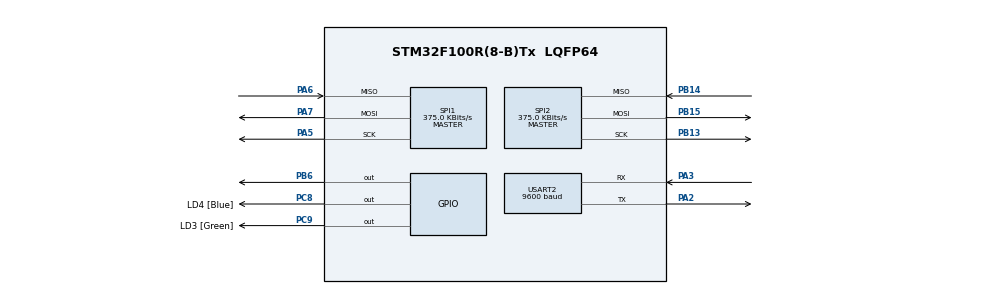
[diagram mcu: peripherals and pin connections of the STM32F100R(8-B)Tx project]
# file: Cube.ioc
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Mcu.Family=STM32F1
Mcu.Name=STM32F100R(8-B)Tx
Mcu.Package=LQFP64
NVIC.PriorityGroup=NVIC_PRIORITYGROUP_4
NVIC.USART2_IRQn=true\:0\:0\:false\:false\:true\:true
PA0-WKUP.Mode=SYS_WakeUp0
PA0-WKUP.Signal=SYS_WKUP
PA13.GPIO_Label=TMS_SWDIO
PA13.Mode=Serial_Wire
PA13.Signal=SYS_JTMS-SWDIO
PA14.GPIO_Label=TCK_SWCLK
PA14.Mode=Serial_Wire
PA14.Signal=SYS_JTCK-SWCLK
PA2.Mode=Asynchronous
PA2.Signal=USART2_TX
PA3.Mode=Asynchronous
PA3.Signal=USART2_RX
PA5.Mode=Full_Duplex_Master
PA5.Signal=SPI1_SCK
PA6.Mode=Full_Duplex_Master
PA6.Signal=SPI1_MISO
PA7.Mode=Full_Duplex_Master
PA7.Signal=SPI1_MOSI
PB13.Mode=Full_Duplex_Master
PB13.Signal=SPI2_SCK
PB14.Mode=Full_Duplex_Master
PB14.Signal=SPI2_MISO
PB15.Mode=Full_Duplex_Master
PB15.Signal=SPI2_MOSI
PB6.Signal=GPIO_Output
PC14-OSC32_IN.Mode=LSE-External-Oscillator
PC14-OSC32_IN.Signal=RCC_OSC32_IN
PC15-OSC32_OUT.Mode=LSE-External-Oscillator
PC15-OSC32_OUT.Signal=RCC_OSC32_OUT
PC8.GPIO_Label=LD4 [Blue]
PC8.Signal=GPIO_Output
PC9.GPIO_Label=LD3 [Green]
PC9.Signal=GPIO_Output
PD0-OSC_IN.Mode=HSE-External-Oscillator
PD0-OSC_IN.Signal=RCC_OSC_IN
PD1-OSC_OUT.Mode=HSE-External-Oscillator
PD1-OSC_OUT.Signal=RCC_OSC_OUT
ProjectManager.HeapSize=0x200
ProjectManager.StackSize=0x400
ProjectManager.TargetToolchain=MDK-ARM V5
RCC.AHBFreq_Value=24000000
RCC.APB1Freq_Value=24000000
RCC.APB1TimFreq_Value=24000000
RCC.APB2Freq_Value=24000000
RCC.APB2TimFreq_Value=24000000
RCC.HCLKFreq_Value=24000000
RCC.PLLMUL=RCC_PLL_MUL3
RCC.PLLSource=RCC_PLLSOURCE_HSE
RCC.SYSCLKFreq_VALUE=24000000
RCC.SYSCLKSource=RCC_SYSCLKSOURCE_PLLCLK
SPI1.BaudRatePrescaler=SPI_BAUDRATEPRESCALER_64
SPI1.CLKPhase=SPI_PHASE_2EDGE
SPI1.CLKPolarity=SPI_POLARITY_HIGH
SPI1.CalculateBaudRate=375.0 KBits/s
SPI1.Direction=SPI_DIRECTION_2LINES
SPI1.Mode=SPI_MODE_MASTER
SPI1.VirtualType=VM_MASTER
SPI2.BaudRatePrescaler=SPI_BAUDRATEPRESCALER_64
SPI2.CLKPhase=SPI_PHASE_2EDGE
SPI2.CLKPolarity=SPI_POLARITY_HIGH
SPI2.CalculateBaudRate=375.0 KBits/s
SPI2.Direction=SPI_DIRECTION_2LINES
SPI2.Mode=SPI_MODE_MASTER
SPI2.VirtualType=VM_MASTER
USART2.BaudRate=9600
USART2.VirtualMode=VM_ASYNC
board=STM32VLDISCOVERY

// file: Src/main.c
/* USER CODE BEGIN Header */
/**
  ******************************************************************************
  * @file           : main.c
  * @brief          : Main program body
  ******************************************************************************
  ** This notice applies to any and all portions of this file
  * that are not between comment pairs USER CODE BEGIN and
  * USER CODE END. Other portions of this file, whether
  * inserted by the user or by software development tools
  * are owned by their respective copyright owners.
  *
  * COPYRIGHT(c) 2019 STMicroelectronics
  *
  * Redistribution and use in source and binary forms, with or without modification,
  * are permitted provided that the following conditions are met:
  *   1. Redistributions of source code must retain the above copyright notice,
  *      this list of conditions and the following disclaimer.
  *   2. Redistributions in binary form must reproduce the above copyright notice,
  *      this list of conditions and the following disclaimer in the documentation
  *      and/or other materials provided with the distribution.
  *   3. Neither the name of STMicroelectronics nor the names of its contributors
  *      may be used to endorse or promote products derived from this software
  *      without specific prior written permission.
  *
  * THIS SOFTWARE IS PROVIDED BY THE COPYRIGHT HOLDERS AND CONTRIBUTORS "AS IS"
  * AND ANY EXPRESS OR IMPLIED WARRANTIES, INCLUDING, BUT NOT LIMITED TO, THE
  * IMPLIED WARRANTIES OF MERCHANTABILITY AND FITNESS FOR A PARTICULAR PURPOSE ARE
  * DISCLAIMED. IN NO EVENT SHALL THE COPYRIGHT HOLDER OR CONTRIBUTORS BE LIABLE
  * FOR ANY DIRECT, INDIRECT, INCIDENTAL, SPECIAL, EXEMPLARY, OR CONSEQUENTIAL
  * DAMAGES (INCLUDING, BUT NOT LIMITED TO, PROCUREMENT OF SUBSTITUTE GOODS OR
  * SERVICES; LOSS OF USE, DATA, OR PROFITS; OR BUSINESS INTERRUPTION) HOWEVER
  * CAUSED AND ON ANY THEORY OF LIABILITY, WHETHER IN CONTRACT, STRICT LIABILITY,
  * OR TORT (INCLUDING NEGLIGENCE OR OTHERWISE) ARISING IN ANY WAY OUT OF THE USE
  * OF THIS SOFTWARE, EVEN IF ADVISED OF THE POSSIBILITY OF SUCH DAMAGE.
  *
  ******************************************************************************
  */
/* USER CODE END Header */

#include "main.h"

/* USER CODE BEGIN Includes */
#include <string.h>
#include "uart.h"
/* USER CODE END Includes */

SPI_HandleTypeDef hspi1;
SPI_HandleTypeDef hspi2;

UART_HandleTypeDef huart2;

/* USER CODE BEGIN PV */
uint8_t data_rec[6];
char num[10];
int16_t x,y,z;
float xg, yg, zg;
/* USER CODE END PV */

void SystemClock_Config(void);
static void MX_GPIO_Init(void);
static void MX_SPI1_Init(void);
static void MX_SPI2_Init(void);
static void MX_USART2_UART_Init(void);

/* USER CODE BEGIN 0 */
void adxl_write (uint8_t address, uint8_t value)
{
	uint8_t data[2];
	data[0] = address|0x40;  // multibyte write enabled
	data[1] = value;
	HAL_GPIO_WritePin (GPIOB, GPIO_PIN_6, GPIO_PIN_RESET); // pull the cs pin low to enable the slave
	HAL_SPI_Transmit (&hspi2, data, 2, 100);  // transmit the address and data
	HAL_GPIO_WritePin (GPIOB, GPIO_PIN_6, GPIO_PIN_SET); // pull the cs pin high to disable the slave
}

void adxl_read (uint8_t address)
{
	address |= 0x80;  // read operation
	address |= 0x40;  // multibyte read
	HAL_GPIO_WritePin (GPIOB, GPIO_PIN_6, GPIO_PIN_RESET);  // pull the cs pin low to enable the slave
	HAL_SPI_Transmit (&hspi2, &address, 1, 100);  // send the address from where you want to read data
	HAL_SPI_Receive (&hspi2, data_rec, 6, 100);  // read 6 BYTES of data
	HAL_GPIO_WritePin (GPIOB, GPIO_PIN_6, GPIO_PIN_SET);  // pull the cs pin high to disable the slave
}

void adxl_init (void)
{
	adxl_write (0x31, 0x01);  // data_format range= +- 4g
	adxl_write (0x2d, 0x00);  // reset all bits
	adxl_write (0x2d, 0x08);  // power_cntl measure and wake up 8hz
}
/* USER CODE END 0 */

int main(void)
{

  /* MCU Configuration--------------------------------------------------------*/

  /* Reset of all peripherals, Initializes the Flash interface and the Systick. */
  HAL_Init();

  /* Configure the system clock */
  SystemClock_Config();

  /* Initialize all configured peripherals */
  MX_GPIO_Init();
  MX_SPI1_Init();
  MX_SPI2_Init();
  MX_USART2_UART_Init();
  /* USER CODE BEGIN 2 */

	adxl_init();  // initialise adxl
  /* USER CODE END 2 */
	print_str("Let the accelerometer be blessed \n\r");
	HAL_Delay(500);
  /* Infinite loop */
  while (1)
  {

    /* USER CODE BEGIN 3 */
//		uint8_t address =45;
//		HAL_GPIO_WritePin (GPIOB, GPIO_PIN_6, GPIO_PIN_RESET); // pull the cs pin low to enable the slave
//		HAL_SPI_Transmit (&hspi2, &address, 1, 100);  // send the address from where you want to read data
//		HAL_GPIO_WritePin (GPIOB, GPIO_PIN_6, GPIO_PIN_SET); // pull the cs pin high to disable the slave

//
		adxl_read (0x32);
	  x = ((data_rec[1]<<8)|data_rec[0]);
    y = ((data_rec[3]<<8)|data_rec[2]);
    z = ((data_rec[5]<<8)|data_rec[4]);

      // Convert into 'g'

    xg = x*.0078;
    yg = y*.0078;
 	  zg = z*.0078;

		print_str("X: ");
		sprintf(num,"%f", xg);
		print_str(num);
		print_str("   Y: ");
		sprintf(num,"%f", yg);
		print_str(num);
		print_str("   Z: ");
		sprintf(num,"%f", zg);
		print_str(num);
		print_str("\n\r");

HAL_Delay (200);   // wait for 200 ms
   	  // display the result on LCD
  }
  /* USER CODE END 3 */
}

void SystemClock_Config(void)
{
  RCC_OscInitTypeDef RCC_OscInitStruct = {0};
  RCC_ClkInitTypeDef RCC_ClkInitStruct = {0};

  /**Initializes the CPU, AHB and APB busses clocks
  */
  RCC_OscInitStruct.OscillatorType = RCC_OSCILLATORTYPE_HSE;
  RCC_OscInitStruct.HSEState = RCC_HSE_ON;
  RCC_OscInitStruct.HSEPredivValue = RCC_HSE_PREDIV_DIV2;
  RCC_OscInitStruct.PLL.PLLState = RCC_PLL_ON;
  RCC_OscInitStruct.PLL.PLLSource = RCC_PLLSOURCE_HSE;
  RCC_OscInitStruct.PLL.PLLMUL = RCC_PLL_MUL5;
  if (HAL_RCC_OscConfig(&RCC_OscInitStruct) != HAL_OK)
  {
    Error_Handler();
  }
  /**Initializes the CPU, AHB and APB busses clocks
  */
  RCC_ClkInitStruct.ClockType = RCC_CLOCKTYPE_HCLK|RCC_CLOCKTYPE_SYSCLK
                              |RCC_CLOCKTYPE_PCLK1|RCC_CLOCKTYPE_PCLK2;
  RCC_ClkInitStruct.SYSCLKSource = RCC_SYSCLKSOURCE_PLLCLK;
  RCC_ClkInitStruct.AHBCLKDivider = RCC_SYSCLK_DIV4;
  RCC_ClkInitStruct.APB1CLKDivider = RCC_HCLK_DIV1;
  RCC_ClkInitStruct.APB2CLKDivider = RCC_HCLK_DIV1;

  if (HAL_RCC_ClockConfig(&RCC_ClkInitStruct, FLASH_LATENCY_0) != HAL_OK)
  {
    Error_Handler();
  }
}

static void MX_SPI1_Init(void)
{

  /* SPI1 parameter configuration*/
  hspi1.Instance = SPI1;
  hspi1.Init.Mode = SPI_MODE_MASTER;
  hspi1.Init.Direction = SPI_DIRECTION_2LINES;
  hspi1.Init.DataSize = SPI_DATASIZE_8BIT;
  hspi1.Init.CLKPolarity = SPI_POLARITY_HIGH;
  hspi1.Init.CLKPhase = SPI_PHASE_2EDGE;
  hspi1.Init.NSS = SPI_NSS_SOFT;
  hspi1.Init.BaudRatePrescaler = SPI_BAUDRATEPRESCALER_64;
  hspi1.Init.FirstBit = SPI_FIRSTBIT_MSB;
  hspi1.Init.TIMode = SPI_TIMODE_DISABLE;
  hspi1.Init.CRCCalculation = SPI_CRCCALCULATION_DISABLE;
  hspi1.Init.CRCPolynomial = 10;
  if (HAL_SPI_Init(&hspi1) != HAL_OK)
  {
    Error_Handler();
  }

}

static void MX_SPI2_Init(void)
{

  /* SPI2 parameter configuration*/
  hspi2.Instance = SPI2;
  hspi2.Init.Mode = SPI_MODE_MASTER;
  hspi2.Init.Direction = SPI_DIRECTION_2LINES;
  hspi2.Init.DataSize = SPI_DATASIZE_8BIT;
  hspi2.Init.CLKPolarity = SPI_POLARITY_HIGH;
  hspi2.Init.CLKPhase = SPI_PHASE_2EDGE;
  hspi2.Init.NSS = SPI_NSS_SOFT;
  hspi2.Init.BaudRatePrescaler = SPI_BAUDRATEPRESCALER_64;
  hspi2.Init.FirstBit = SPI_FIRSTBIT_MSB;
  hspi2.Init.TIMode = SPI_TIMODE_DISABLE;
  hspi2.Init.CRCCalculation = SPI_CRCCALCULATION_DISABLE;
  hspi2.Init.CRCPolynomial = 10;
  if (HAL_SPI_Init(&hspi2) != HAL_OK)
  {
    Error_Handler();
  }

}

static void MX_USART2_UART_Init(void)
{

  huart2.Instance = USART2;
  huart2.Init.BaudRate = 9600;
  huart2.Init.WordLength = UART_WORDLENGTH_8B;
  huart2.Init.StopBits = UART_STOPBITS_1;
  huart2.Init.Parity = UART_PARITY_NONE;
  huart2.Init.Mode = UART_MODE_TX_RX;
  huart2.Init.HwFlowCtl = UART_HWCONTROL_NONE;
  huart2.Init.OverSampling = UART_OVERSAMPLING_16;
  if (HAL_UART_Init(&huart2) != HAL_OK)
  {
    Error_Handler();
  }

}

static void MX_GPIO_Init(void)
{
  GPIO_InitTypeDef GPIO_InitStruct = {0};

  /* GPIO Ports Clock Enable */
  __HAL_RCC_GPIOC_CLK_ENABLE();
  __HAL_RCC_GPIOD_CLK_ENABLE();
  __HAL_RCC_GPIOA_CLK_ENABLE();
  __HAL_RCC_GPIOB_CLK_ENABLE();

  /*Configure GPIO pin Output Level */
  HAL_GPIO_WritePin(GPIOC, LD4_Pin|LD3_Pin, GPIO_PIN_RESET);

  /*Configure GPIO pin Output Level */
  HAL_GPIO_WritePin(GPIOB, GPIO_PIN_6, GPIO_PIN_RESET);

  /*Configure GPIO pins : LD4_Pin LD3_Pin */
  GPIO_InitStruct.Pin = LD4_Pin|LD3_Pin;
  GPIO_InitStruct.Mode = GPIO_MODE_OUTPUT_PP;
  GPIO_InitStruct.Pull = GPIO_NOPULL;
  GPIO_InitStruct.Speed = GPIO_SPEED_FREQ_LOW;
  HAL_GPIO_Init(GPIOC, &GPIO_InitStruct);

  /*Configure GPIO pin : PB6 */
  GPIO_InitStruct.Pin = GPIO_PIN_6;
  GPIO_InitStruct.Mode = GPIO_MODE_OUTPUT_PP;
  GPIO_InitStruct.Pull = GPIO_NOPULL;
  GPIO_InitStruct.Speed = GPIO_SPEED_FREQ_LOW;
  HAL_GPIO_Init(GPIOB, &GPIO_InitStruct);

}

void Error_Handler(void)
{
}

/************************ (C) COPYRIGHT STMicroelectronics *****END OF FILE****/
